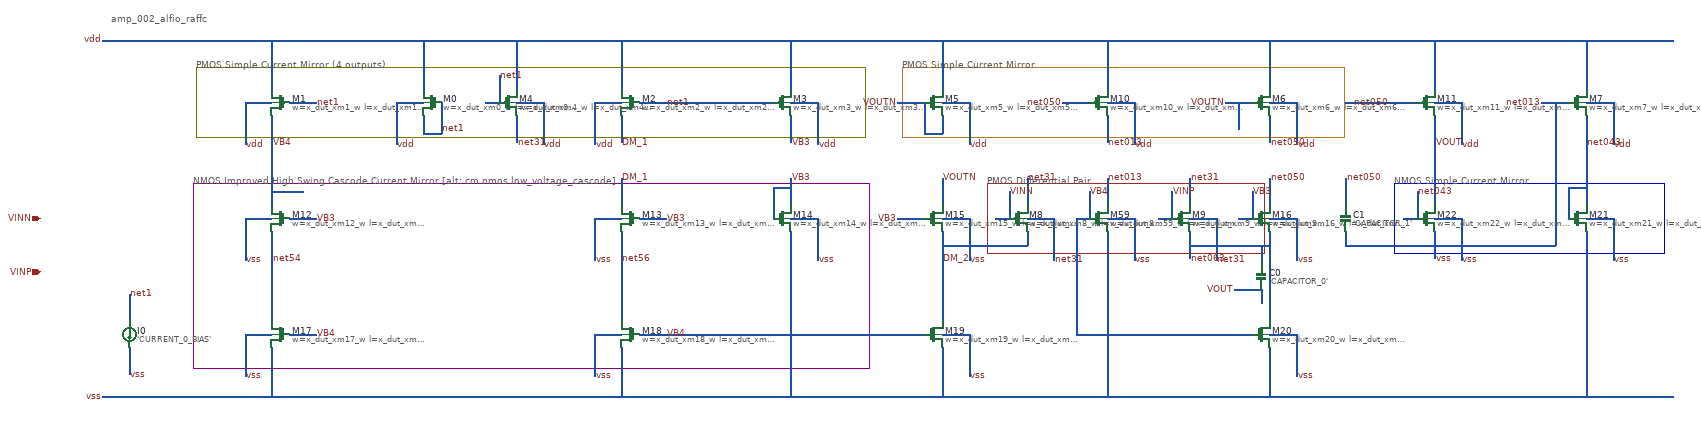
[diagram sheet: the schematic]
v {xschem version=3.4.6 file_version=1.2}
G {}
K {}
V {}
S {}
E {}
T {amp_002_alfio_raffc} -1740 -200 0 0 0.4 0.4 {}
C {devices/capa_np.sym} 840 390 0 0 {name=C0 value='CAPACITOR_0'}
C {devices/capa_np.sym} 1030 260 0 0 {name=C1 value='CAPACITOR_1'}
C {devices/isource_np.sym} -1700 520 0 0 {name=I0 value='CURRENT_0_BIAS'}
C {devices/sg13_lv_pmos_np.sym} -1020 0 0 1 {name=M0 model=sg13_lv_pmos spiceprefix=X w=x_dut_xm0_w l=x_dut_xm0_l m=x_dut_xm0_m}
C {devices/sg13_lv_pmos_np.sym} -1360 0 0 1 {name=M1 model=sg13_lv_pmos spiceprefix=X w=x_dut_xm1_w l=x_dut_xm1_l m=x_dut_xm1_m}
C {devices/sg13_lv_pmos_np.sym} 475 0 0 0 {name=M10 model=sg13_lv_pmos spiceprefix=X w=x_dut_xm10_w l=x_dut_xm10_l m=x_dut_xm10_m}
C {devices/sg13_lv_pmos_np.sym} 1210 0 0 0 {name=M11 model=sg13_lv_pmos spiceprefix=X w=x_dut_xm11_w l=x_dut_xm11_l m=x_dut_xm11_m}
C {devices/sg13_lv_nmos_np.sym} -1360 260 0 1 {name=M12 model=sg13_lv_nmos spiceprefix=X w=x_dut_xm12_w l=x_dut_xm12_l m=x_dut_xm12_m}
C {devices/sg13_lv_nmos_np.sym} -575 260 0 1 {name=M13 model=sg13_lv_nmos spiceprefix=X w=x_dut_xm13_w l=x_dut_xm13_l m=x_dut_xm13_m}
C {devices/sg13_lv_nmos_np.sym} -235 260 0 0 {name=M14 model=sg13_lv_nmos spiceprefix=X w=x_dut_xm14_w l=x_dut_xm14_l m=x_dut_xm14_m}
C {devices/sg13_lv_nmos_np.sym} 105 260 0 0 {name=M15 model=sg13_lv_nmos spiceprefix=X w=x_dut_xm15_w l=x_dut_xm15_l m=x_dut_xm15_m}
C {devices/sg13_lv_nmos_np.sym} 840 260 0 0 {name=M16 model=sg13_lv_nmos spiceprefix=X w=x_dut_xm16_w l=x_dut_xm16_l m=x_dut_xm16_m}
C {devices/sg13_lv_nmos_np.sym} -1360 520 0 1 {name=M17 model=sg13_lv_nmos spiceprefix=X w=x_dut_xm17_w l=x_dut_xm17_l m=x_dut_xm17_m}
C {devices/sg13_lv_nmos_np.sym} -575 520 0 1 {name=M18 model=sg13_lv_nmos spiceprefix=X w=x_dut_xm18_w l=x_dut_xm18_l m=x_dut_xm18_m}
C {devices/sg13_lv_nmos_np.sym} 105 520 0 0 {name=M19 model=sg13_lv_nmos spiceprefix=X w=x_dut_xm19_w l=x_dut_xm19_l m=x_dut_xm19_m}
C {devices/sg13_lv_pmos_np.sym} -575 0 0 1 {name=M2 model=sg13_lv_pmos spiceprefix=X w=x_dut_xm2_w l=x_dut_xm2_l m=x_dut_xm2_m}
C {devices/sg13_lv_nmos_np.sym} 840 520 0 0 {name=M20 model=sg13_lv_nmos spiceprefix=X w=x_dut_xm20_w l=x_dut_xm20_l m=x_dut_xm20_m}
C {devices/sg13_lv_nmos_np.sym} 1550 260 0 0 {name=M21 model=sg13_lv_nmos spiceprefix=X w=x_dut_xm21_w l=x_dut_xm21_l m=x_dut_xm21_m}
C {devices/sg13_lv_nmos_np.sym} 1210 260 0 0 {name=M22 model=sg13_lv_nmos spiceprefix=X w=x_dut_xm22_w l=x_dut_xm22_l m=x_dut_xm22_m}
C {devices/sg13_lv_pmos_np.sym} -235 0 0 0 {name=M3 model=sg13_lv_pmos spiceprefix=X w=x_dut_xm3_w l=x_dut_xm3_l m=x_dut_xm3_m}
C {devices/sg13_lv_pmos_np.sym} -850 0 0 0 {name=M4 model=sg13_lv_pmos spiceprefix=X w=x_dut_xm4_w l=x_dut_xm4_l m=x_dut_xm4_m}
C {devices/sg13_lv_pmos_np.sym} 105 0 0 0 {name=M5 model=sg13_lv_pmos spiceprefix=X w=x_dut_xm5_w l=x_dut_xm5_l m=x_dut_xm5_m}
C {devices/sg13_lv_nmos_np.sym} 475 260 0 0 {name=M59 model=sg13_lv_nmos spiceprefix=X w=x_dut_xm59_w l=x_dut_xm59_l m=x_dut_xm59_m}
C {devices/sg13_lv_pmos_np.sym} 840 0 0 0 {name=M6 model=sg13_lv_pmos spiceprefix=X w=x_dut_xm6_w l=x_dut_xm6_l m=x_dut_xm6_m}
C {devices/sg13_lv_pmos_np.sym} 1550 0 0 0 {name=M7 model=sg13_lv_pmos spiceprefix=X w=x_dut_xm7_w l=x_dut_xm7_l m=x_dut_xm7_m}
C {devices/sg13_lv_pmos_np.sym} 295 260 0 0 {name=M8 model=sg13_lv_pmos spiceprefix=X w=x_dut_xm8_w l=x_dut_xm8_l m=x_dut_xm8_m}
C {devices/sg13_lv_pmos_np.sym} 660 260 0 0 {name=M9 model=sg13_lv_pmos spiceprefix=X w=x_dut_xm9_w l=x_dut_xm9_l m=x_dut_xm9_m}
N -1700 430 -1700 490 {}
N -1700 550 -1700 610 {}
N -1440 0 -1440 94 {}
N -1440 260 -1440 354 {}
N -1440 520 -1440 614 {}
N -1380 -140 -1380 -30 {}
N -1380 30 -1380 230 {}
N -1380 290 -1380 490 {}
N -1380 550 -1380 660 {}
N -1100 0 -1100 94 {}
N -1040 -140 -1040 -30 {}
N -1040 30 -1040 70 {}
N -1000 0 -1000 70 {}
N -870 -60 -870 0 {}
N -830 -140 -830 -30 {}
N -830 30 -830 90 {}
N -770 0 -770 94 {}
N -655 0 -655 94 {}
N -655 260 -655 354 {}
N -655 520 -655 614 {}
N -595 -140 -595 -30 {}
N -595 30 -595 90 {}
N -595 170 -595 230 {}
N -595 290 -595 490 {}
N -595 550 -595 660 {}
N -255 190 -255 260 {}
N -215 -140 -215 -30 {}
N -215 30 -215 90 {}
N -215 170 -215 230 {}
N -215 290 -215 660 {}
N -155 0 -155 94 {}
N -155 260 -155 354 {}
N 85 0 85 70 {}
N 125 -140 125 -30 {}
N 125 30 125 70 {}
N 125 170 125 230 {}
N 125 290 125 490 {}
N 125 550 125 660 {}
N 185 0 185 94 {}
N 185 260 185 354 {}
N 185 520 185 614 {}
N 275 200 275 260 {}
N 315 170 315 230 {}
N 315 290 315 320 {}
N 375 260 375 354 {}
N 425 260 425 520 {}
N 455 200 455 260 {}
N 495 -140 495 -30 {}
N 495 30 495 90 {}
N 495 170 495 230 {}
N 495 290 495 660 {}
N 555 0 555 94 {}
N 555 260 555 354 {}
N 640 200 640 260 {}
N 680 170 680 230 {}
N 680 290 680 350 {}
N 740 260 740 354 {}
N 790 0 790 60 {}
N 820 200 820 260 {}
N 840 320 840 360 {}
N 840 420 840 450 {}
N 860 -140 860 -30 {}
N 860 30 860 90 {}
N 860 170 860 230 {}
N 860 290 860 490 {}
N 860 550 860 660 {}
N 920 0 920 94 {}
N 920 260 920 354 {}
N 920 520 920 614 {}
N 1030 170 1030 230 {}
N 1030 290 1030 320 {}
N 1190 200 1190 260 {}
N 1230 -140 1230 -30 {}
N 1230 30 1230 230 {}
N 1230 290 1230 350 {}
N 1290 0 1290 94 {}
N 1290 260 1290 354 {}
N 1500 0 1500 320 {}
N 1530 190 1530 260 {}
N 1570 -140 1570 -30 {}
N 1570 30 1570 230 {}
N 1570 290 1570 660 {}
N 1630 0 1630 94 {}
N 1630 260 1630 354 {}
N -1760 -140 1765 -140 {}
N -1440 0 -1380 0 {}
N -1340 0 -1280 0 {}
N -1100 0 -1040 0 {}
N -900 0 -870 0 {}
N -830 0 -770 0 {}
N -655 0 -595 0 {}
N -555 0 -255 0 {}
N -215 0 -155 0 {}
N 25 0 85 0 {}
N 125 0 185 0 {}
N 395 0 455 0 {}
N 495 0 555 0 {}
N 760 0 820 0 {}
N 860 0 920 0 {}
N 1030 0 1190 0 {}
N 1230 0 1290 0 {}
N 1470 0 1530 0 {}
N 1570 0 1630 0 {}
N -1040 70 -1000 70 {}
N 85 70 125 70 {}
N -255 190 -215 190 {}
N 1530 190 1570 190 {}
N -1380 200 -1310 200 {}
N -1440 260 -1380 260 {}
N -1340 260 -1280 260 {}
N -655 260 -595 260 {}
N -555 260 -495 260 {}
N -215 260 -155 260 {}
N 25 260 85 260 {}
N 125 260 185 260 {}
N 245 260 275 260 {}
N 315 260 375 260 {}
N 425 260 455 260 {}
N 495 260 555 260 {}
N 610 260 640 260 {}
N 680 260 740 260 {}
N 790 260 820 260 {}
N 860 260 920 260 {}
N 1160 260 1190 260 {}
N 1230 260 1290 260 {}
N 1570 260 1630 260 {}
N 125 320 315 320 {}
N 680 320 860 320 {}
N 1030 320 1500 320 {}
N 780 420 840 420 {}
N -1440 520 -1380 520 {}
N -1340 520 -1280 520 {}
N -655 520 -595 520 {}
N -555 520 85 520 {}
N 125 520 185 520 {}
N 425 520 820 520 {}
N 860 520 920 520 {}
N -1760 660 1765 660 {}
C {devices/lab_wire.sym} -1760 -140 0 0 {name=l0 lab=vdd}
C {devices/lab_wire.sym} -1760 660 0 0 {name=l1 lab=vss}
C {devices/lab_wire.sym} -595 90 2 0 {name=l2 lab=DM_1}
C {devices/lab_wire.sym} -595 170 0 1 {name=l3 lab=DM_1}
C {devices/lab_wire.sym} 125 350 2 0 {name=l4 lab=DM_2}
C {devices/lab_wire.sym} -1280 260 0 1 {name=l5 lab=VB3}
C {devices/lab_wire.sym} -495 260 0 1 {name=l6 lab=VB3}
C {devices/lab_wire.sym} -215 170 0 1 {name=l7 lab=VB3}
C {devices/lab_wire.sym} -215 90 2 0 {name=l8 lab=VB3}
C {devices/lab_wire.sym} 25 260 0 0 {name=l9 lab=VB3}
C {devices/lab_wire.sym} 820 200 0 1 {name=l10 lab=VB3}
C {devices/lab_wire.sym} -1380 90 2 0 {name=l11 lab=VB4}
C {devices/lab_wire.sym} -1280 520 0 1 {name=l12 lab=VB4}
C {devices/lab_wire.sym} -495 520 0 1 {name=l13 lab=VB4}
C {devices/lab_wire.sym} 455 200 0 1 {name=l14 lab=VB4}
C {devices/lab_wire.sym} 275 200 0 1 {name=l15 lab=VINN}
C {devices/lab_wire.sym} 640 200 0 1 {name=l16 lab=VINP}
C {devices/lab_wire.sym} 780 420 0 0 {name=l17 lab=VOUT}
C {devices/lab_wire.sym} 1230 90 2 0 {name=l18 lab=VOUT}
C {devices/lab_wire.sym} 25 0 0 0 {name=l19 lab=VOUTN}
C {devices/lab_wire.sym} 125 170 0 1 {name=l20 lab=VOUTN}
C {devices/lab_wire.sym} 760 0 0 0 {name=l21 lab=VOUTN}
C {devices/lab_wire.sym} 495 90 2 0 {name=l22 lab=net013}
C {devices/lab_wire.sym} 495 170 0 1 {name=l23 lab=net013}
C {devices/lab_wire.sym} 1470 0 0 0 {name=l24 lab=net013}
C {devices/lab_wire.sym} 1190 200 0 1 {name=l25 lab=net043}
C {devices/lab_wire.sym} 1570 90 2 0 {name=l26 lab=net043}
C {devices/lab_wire.sym} 395 0 0 0 {name=l27 lab=net050}
C {devices/lab_wire.sym} 860 90 2 0 {name=l28 lab=net050}
C {devices/lab_wire.sym} 860 170 0 1 {name=l29 lab=net050}
C {devices/lab_wire.sym} 1030 170 0 1 {name=l30 lab=net050}
C {devices/lab_wire.sym} 1130 0 0 0 {name=l31 lab=net050}
C {devices/lab_wire.sym} 680 350 2 0 {name=l32 lab=net063}
C {devices/lab_wire.sym} -1280 0 0 1 {name=l33 lab=net1}
C {devices/lab_wire.sym} -1000 60 2 0 {name=l34 lab=net1}
C {devices/lab_wire.sym} -870 -60 0 1 {name=l35 lab=net1}
C {devices/lab_wire.sym} -495 0 0 1 {name=l36 lab=net1}
C {devices/lab_wire.sym} -830 90 2 0 {name=l37 lab=net31}
C {devices/lab_wire.sym} 315 170 0 1 {name=l38 lab=net31}
C {devices/lab_wire.sym} 680 170 0 1 {name=l39 lab=net31}
C {devices/lab_wire.sym} -1380 350 2 0 {name=l40 lab=net54}
C {devices/lab_wire.sym} -595 350 2 0 {name=l41 lab=net56}
C {devices/lab_wire.sym} 375 354 2 0 {name=l42 lab=net31}
C {devices/lab_wire.sym} 740 354 2 0 {name=l43 lab=net31}
C {devices/lab_wire.sym} -1100 94 2 0 {name=l44 lab=vdd}
C {devices/lab_wire.sym} -1440 94 2 0 {name=l45 lab=vdd}
C {devices/lab_wire.sym} 555 94 2 0 {name=l46 lab=vdd}
C {devices/lab_wire.sym} 1290 94 2 0 {name=l47 lab=vdd}
C {devices/lab_wire.sym} -655 94 2 0 {name=l48 lab=vdd}
C {devices/lab_wire.sym} -155 94 2 0 {name=l49 lab=vdd}
C {devices/lab_wire.sym} -770 94 2 0 {name=l50 lab=vdd}
C {devices/lab_wire.sym} 185 94 2 0 {name=l51 lab=vdd}
C {devices/lab_wire.sym} 920 94 2 0 {name=l52 lab=vdd}
C {devices/lab_wire.sym} 1630 94 2 0 {name=l53 lab=vdd}
C {devices/lab_wire.sym} -1440 354 2 0 {name=l54 lab=vss}
C {devices/lab_wire.sym} -655 354 2 0 {name=l55 lab=vss}
C {devices/lab_wire.sym} -155 354 2 0 {name=l56 lab=vss}
C {devices/lab_wire.sym} 185 354 2 0 {name=l57 lab=vss}
C {devices/lab_wire.sym} 920 354 2 0 {name=l58 lab=vss}
C {devices/lab_wire.sym} -1440 614 2 0 {name=l59 lab=vss}
C {devices/lab_wire.sym} -655 614 2 0 {name=l60 lab=vss}
C {devices/lab_wire.sym} 185 614 2 0 {name=l61 lab=vss}
C {devices/lab_wire.sym} 920 614 2 0 {name=l62 lab=vss}
C {devices/lab_wire.sym} 1630 354 2 0 {name=l63 lab=vss}
C {devices/lab_wire.sym} 1290 354 2 0 {name=l64 lab=vss}
C {devices/lab_wire.sym} 555 354 2 0 {name=l65 lab=vss}
C {devices/lab_wire.sym} -1700 430 0 1 {name=l66 lab=net1}
C {devices/lab_wire.sym} -1700 610 2 0 {name=l67 lab=vss}
C {devices/lab_wire.sym} 1230 350 2 0 {name=l68 lab=vss}
C {devices/ipin.sym} -1900 260 0 0 {name=p0 lab=VINN}
C {devices/ipin.sym} -1900 380 0 0 {name=p1 lab=VINP}
B 8 -1548 -78 -47 78 {fill=0}
T {PMOS Simple Current Mirror (4 outputs)} -1548 -96 0 0 0.3 0.3 {layer=8}
B 10 -1556 182 -39 598 {fill=0}
T {NMOS Improved High Swing Cascode Current Mirror [alt: cm.nmos.low_voltage_cascode]} -1556 164 0 0 0.3 0.3 {layer=10}
B 12 1140 182 1746 338 {fill=0}
T {NMOS Simple Current Mirror} 1140 164 0 0 0.3 0.3 {layer=12}
B 21 35 -78 1028 78 {fill=0}
T {PMOS Simple Current Mirror} 35 -96 0 0 0.3 0.3 {layer=21}
B 15 225 182 848 338 {fill=0}
T {PMOS Differential Pair} 225 164 0 0 0.3 0.3 {layer=15}
